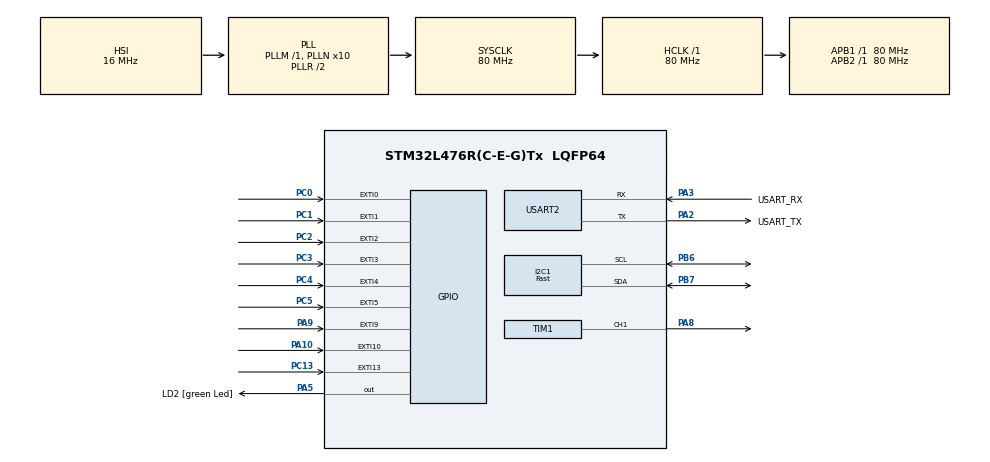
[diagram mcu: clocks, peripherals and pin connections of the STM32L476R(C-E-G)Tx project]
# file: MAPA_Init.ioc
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Dma.Request0=TIM1_CH1
Dma.TIM1_CH1.0.Direction=DMA_MEMORY_TO_PERIPH
Dma.TIM1_CH1.0.Instance=DMA1_Channel2
Dma.TIM1_CH1.0.MemDataAlignment=DMA_MDATAALIGN_HALFWORD
Dma.TIM1_CH1.0.MemInc=DMA_MINC_ENABLE
Dma.TIM1_CH1.0.Mode=DMA_NORMAL
Dma.TIM1_CH1.0.PeriphDataAlignment=DMA_PDATAALIGN_HALFWORD
Dma.TIM1_CH1.0.PeriphInc=DMA_PINC_DISABLE
Dma.TIM1_CH1.0.Priority=DMA_PRIORITY_VERY_HIGH
I2C1.I2C_Speed_Mode=I2C_Fast
I2C1.Timing=0x00702991
Mcu.Family=STM32L4
Mcu.Name=STM32L476R(C-E-G)Tx
Mcu.Package=LQFP64
NVIC.DMA1_Channel2_IRQn=true\:0\:0\:false\:false\:true\:false\:true\:true
NVIC.EXTI0_IRQn=true\:0\:0\:false\:false\:true\:true\:true\:true
NVIC.EXTI15_10_IRQn=true\:0\:0\:false\:false\:true\:true\:true\:true
NVIC.EXTI1_IRQn=true\:0\:0\:false\:false\:true\:true\:true\:true
NVIC.EXTI9_5_IRQn=true\:0\:0\:false\:false\:true\:true\:true\:true
NVIC.PriorityGroup=NVIC_PRIORITYGROUP_4
PA10.GPIO_ModeDefaultEXTI=GPIO_MODE_IT_FALLING
PA10.GPIO_PuPd=GPIO_PULLUP
PA10.Signal=GPXTI10
PA14\ (JTCK-SWCLK).GPIO_Label=TCK
PA14\ (JTCK-SWCLK).Signal=SYS_JTCK-SWCLK
PA2.GPIO_Label=USART_TX
PA2.GPIO_Mode=GPIO_MODE_AF_PP
PA2.GPIO_PuPd=GPIO_NOPULL
PA2.GPIO_Speed=GPIO_SPEED_FREQ_VERY_HIGH
PA2.Mode=Asynchronous
PA2.Signal=USART2_TX
PA3.GPIO_Label=USART_RX
PA3.GPIO_Mode=GPIO_MODE_AF_PP
PA3.GPIO_PuPd=GPIO_NOPULL
PA3.GPIO_Speed=GPIO_SPEED_FREQ_VERY_HIGH
PA3.Mode=Asynchronous
PA3.Signal=USART2_RX
PA5.GPIO_Label=LD2 [green Led]
PA5.GPIO_ModeDefaultOutputPP=GPIO_MODE_OUTPUT_PP
PA5.GPIO_PuPd=GPIO_PULLUP
PA5.GPIO_Speed=GPIO_SPEED_FREQ_LOW
PA5.Signal=GPIO_Output
PA8.Signal=S_TIM1_CH1
PA9.GPIO_ModeDefaultEXTI=GPIO_MODE_IT_FALLING
PA9.GPIO_PuPd=GPIO_PULLUP
PA9.Signal=GPXTI9
PB3\ (JTDO-TRACESWO).GPIO_Label=SWO
PB3\ (JTDO-TRACESWO).Signal=SYS_JTDO-SWO
PB6.GPIO_Pu=GPIO_PULLUP
PB6.Mode=I2C
PB6.Signal=I2C1_SCL
PB7.GPIO_Pu=GPIO_PULLUP
PB7.Mode=I2C
PB7.Signal=I2C1_SDA
PC0.GPIO_PuPd=GPIO_PULLUP
PC0.Signal=GPXTI0
PC1.GPIO_PuPd=GPIO_PULLUP
PC1.Signal=GPXTI1
PC13.GPIO_ModeDefaultEXTI=GPIO_MODE_IT_FALLING
PC13.GPIO_PuPd=GPIO_PULLUP
PC13.Signal=GPXTI13
PC2.GPIO_PuPd=GPIO_PULLUP
PC2.Signal=GPXTI2
PC3.GPIO_PuPd=GPIO_PULLUP
PC3.Signal=GPXTI3
PC4.GPIO_PuPd=GPIO_PULLUP
PC4.Signal=GPXTI4
PC5.GPIO_PuPd=GPIO_PULLUP
PC5.Signal=GPXTI5
PH0-OSC_IN\ (PH0).Signal=RCC_OSC_IN
PH1-OSC_OUT\ (PH1).Signal=RCC_OSC_OUT
ProjectManager.HeapSize=0x200
ProjectManager.StackSize=0x400
ProjectManager.TargetToolchain=STM32CubeIDE
RCC.ADCFreq_Value=64000000
RCC.AHBFreq_Value=80000000
RCC.APB1Freq_Value=80000000
RCC.APB1TimFreq_Value=80000000
RCC.APB2Freq_Value=80000000
RCC.APB2TimFreq_Value=80000000
RCC.CortexFreq_Value=80000000
RCC.HCLKFreq_Value=80000000
RCC.HSE_VALUE=8000000
RCC.HSI_VALUE=16000000
RCC.LSE_VALUE=32768
RCC.MSI_VALUE=4000000
RCC.PLLN=10
RCC.PLLSourceVirtual=RCC_PLLSOURCE_HSI
RCC.PREFETCH_ENABLE=1
RCC.SYSCLKFreq_VALUE=80000000
RCC.SYSCLKSource=RCC_SYSCLKSOURCE_PLLCLK
RCC.USBFreq_Value=64000000
RCC.VCOOutputFreq_Value=160000000
SH.S_TIM1_CH1.0=TIM1_CH1,PWM Generation1 CH1
TIM1.Channel-PWM\ Generation1\ CH1=TIM_CHANNEL_1
TIM1.Period=199
USART2.VirtualMode-Asynchronous=VM_ASYNC
VP_TIM1_VS_ClockSourceINT.Mode=Internal
board=NUCLEO-L476RG

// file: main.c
/* USER CODE BEGIN Header */
/**
  ******************************************************************************
  * @file           : main.c
  * @brief          : Main program body
  ******************************************************************************
  * @attention
  *
  * Copyright (c) 2024 STMicroelectronics.
  * All rights reserved.
  *
  * This software is licensed under terms that can be found in the LICENSE file
  * in the root directory of this software component.
  * If no LICENSE file comes with this software, it is provided AS-IS.
  *
  ******************************************************************************
  */
/* USER CODE END Header */
#include "main.h"

/* USER CODE BEGIN Includes */
#include "stm32l4xx_hal.h"
#include "brillez.h"
#include "ecran.h"
#include "string.h"
#include <stdio.h>
#include "midi_parser.h"
#include "init.h"
/* USER CODE END Includes */

I2C_HandleTypeDef hi2c1;

TIM_HandleTypeDef htim1;
DMA_HandleTypeDef hdma_tim1_ch1;

UART_HandleTypeDef huart2;

/* USER CODE BEGIN PV */
int __io_putchar(int ch) {
    HAL_UART_Transmit(&huart2, (uint8_t *)&ch, 1, HAL_MAX_DELAY);
    return ch;
}

/* USER CODE END PV */

void SystemClock_Config(void);
static void MX_GPIO_Init(void);
static void MX_DMA_Init(void);
static void MX_USART2_UART_Init(void);
static void MX_TIM1_Init(void);
static void MX_I2C1_Init(void);

int main(void)
{

  /* MCU Configuration--------------------------------------------------------*/

  /* Reset of all peripherals, Initializes the Flash interface and the Systick. */
  HAL_Init();

  /* Configure the system clock */
  SystemClock_Config();

  /* Initialize all configured peripherals */
  MX_GPIO_Init();
  MX_DMA_Init();
  MX_USART2_UART_Init();
  MX_TIM1_Init();
  MX_I2C1_Init();
  /* USER CODE BEGIN 2 */
  brillez_init();

  LCD_Init();
  LCD_Clear();

	LCD_SetRGB(40, 130, 255);  // Bleu

     // Boucle principale

  /* USER CODE END 2 */

  /* Infinite loop */
  /* USER CODE BEGIN WHILE */
	  assignement();
	  printf("fin assignement \r\n");

	  Navigation();

  while (1)
  {

/*			HAL_Delay(50);

	  		LCD_Clear();  // Efface l’écran avant d’écrire

	  		LCD_PrintFormatted("LED numero %lu", compteur);  // Affiche le compteur
	  		HAL_Delay(500);

	  		printf("Liste des sauvegardes : ");
	  		for (uint32_t i = 0; i < sauvegarde_index; i++) {
	  		  printf("%ld ", compteur_sauvegarde[i]);
	  		}
	  		printf("\r\n");

	  		light_up_led(compteur, 0xFF0000, 100);

	  		for (uint32_t i = 0; i < sauvegarde_index; i++) {
	  		  ws2812b_set_led_hex(&h_ws2812b,compteur_sauvegarde[i], 0x00FF00);
	  		}
*/

    /* USER CODE END WHILE */

  }
}

void SystemClock_Config(void)
{
  RCC_OscInitTypeDef RCC_OscInitStruct = {0};
  RCC_ClkInitTypeDef RCC_ClkInitStruct = {0};

  /** Configure the main internal regulator output voltage
  */
  if (HAL_PWREx_ControlVoltageScaling(PWR_REGULATOR_VOLTAGE_SCALE1) != HAL_OK)
  {
    Error_Handler();
  }

  /** Initializes the RCC Oscillators according to the specified parameters
  * in the RCC_OscInitTypeDef structure.
  */
  RCC_OscInitStruct.OscillatorType = RCC_OSCILLATORTYPE_HSI;
  RCC_OscInitStruct.HSIState = RCC_HSI_ON;
  RCC_OscInitStruct.HSICalibrationValue = RCC_HSICALIBRATION_DEFAULT;
  RCC_OscInitStruct.PLL.PLLState = RCC_PLL_ON;
  RCC_OscInitStruct.PLL.PLLSource = RCC_PLLSOURCE_HSI;
  RCC_OscInitStruct.PLL.PLLM = 1;
  RCC_OscInitStruct.PLL.PLLN = 10;
  RCC_OscInitStruct.PLL.PLLP = RCC_PLLP_DIV7;
  RCC_OscInitStruct.PLL.PLLQ = RCC_PLLQ_DIV2;
  RCC_OscInitStruct.PLL.PLLR = RCC_PLLR_DIV2;
  if (HAL_RCC_OscConfig(&RCC_OscInitStruct) != HAL_OK)
  {
    Error_Handler();
  }

  /** Initializes the CPU, AHB and APB buses clocks
  */
  RCC_ClkInitStruct.ClockType = RCC_CLOCKTYPE_HCLK|RCC_CLOCKTYPE_SYSCLK
                              |RCC_CLOCKTYPE_PCLK1|RCC_CLOCKTYPE_PCLK2;
  RCC_ClkInitStruct.SYSCLKSource = RCC_SYSCLKSOURCE_PLLCLK;
  RCC_ClkInitStruct.AHBCLKDivider = RCC_SYSCLK_DIV1;
  RCC_ClkInitStruct.APB1CLKDivider = RCC_HCLK_DIV1;
  RCC_ClkInitStruct.APB2CLKDivider = RCC_HCLK_DIV1;

  if (HAL_RCC_ClockConfig(&RCC_ClkInitStruct, FLASH_LATENCY_4) != HAL_OK)
  {
    Error_Handler();
  }
}

static void MX_I2C1_Init(void)
{

  hi2c1.Instance = I2C1;
  hi2c1.Init.Timing = 0x00702991;
  hi2c1.Init.OwnAddress1 = 0;
  hi2c1.Init.AddressingMode = I2C_ADDRESSINGMODE_7BIT;
  hi2c1.Init.DualAddressMode = I2C_DUALADDRESS_DISABLE;
  hi2c1.Init.OwnAddress2 = 0;
  hi2c1.Init.OwnAddress2Masks = I2C_OA2_NOMASK;
  hi2c1.Init.GeneralCallMode = I2C_GENERALCALL_DISABLE;
  hi2c1.Init.NoStretchMode = I2C_NOSTRETCH_DISABLE;
  if (HAL_I2C_Init(&hi2c1) != HAL_OK)
  {
    Error_Handler();
  }

  /** Configure Analogue filter
  */
  if (HAL_I2CEx_ConfigAnalogFilter(&hi2c1, I2C_ANALOGFILTER_ENABLE) != HAL_OK)
  {
    Error_Handler();
  }

  /** Configure Digital filter
  */
  if (HAL_I2CEx_ConfigDigitalFilter(&hi2c1, 0) != HAL_OK)
  {
    Error_Handler();
  }

}

static void MX_TIM1_Init(void)
{

  TIM_ClockConfigTypeDef sClockSourceConfig = {0};
  TIM_MasterConfigTypeDef sMasterConfig = {0};
  TIM_OC_InitTypeDef sConfigOC = {0};
  TIM_BreakDeadTimeConfigTypeDef sBreakDeadTimeConfig = {0};

  htim1.Instance = TIM1;
  htim1.Init.Prescaler = 0;
  htim1.Init.CounterMode = TIM_COUNTERMODE_UP;
  htim1.Init.Period = 199;
  htim1.Init.ClockDivision = TIM_CLOCKDIVISION_DIV1;
  htim1.Init.RepetitionCounter = 0;
  htim1.Init.AutoReloadPreload = TIM_AUTORELOAD_PRELOAD_DISABLE;
  if (HAL_TIM_Base_Init(&htim1) != HAL_OK)
  {
    Error_Handler();
  }
  sClockSourceConfig.ClockSource = TIM_CLOCKSOURCE_INTERNAL;
  if (HAL_TIM_ConfigClockSource(&htim1, &sClockSourceConfig) != HAL_OK)
  {
    Error_Handler();
  }
  if (HAL_TIM_PWM_Init(&htim1) != HAL_OK)
  {
    Error_Handler();
  }
  sMasterConfig.MasterOutputTrigger = TIM_TRGO_RESET;
  sMasterConfig.MasterOutputTrigger2 = TIM_TRGO2_RESET;
  sMasterConfig.MasterSlaveMode = TIM_MASTERSLAVEMODE_DISABLE;
  if (HAL_TIMEx_MasterConfigSynchronization(&htim1, &sMasterConfig) != HAL_OK)
  {
    Error_Handler();
  }
  sConfigOC.OCMode = TIM_OCMODE_PWM1;
  sConfigOC.Pulse = 0;
  sConfigOC.OCPolarity = TIM_OCPOLARITY_HIGH;
  sConfigOC.OCNPolarity = TIM_OCNPOLARITY_HIGH;
  sConfigOC.OCFastMode = TIM_OCFAST_DISABLE;
  sConfigOC.OCIdleState = TIM_OCIDLESTATE_RESET;
  sConfigOC.OCNIdleState = TIM_OCNIDLESTATE_RESET;
  if (HAL_TIM_PWM_ConfigChannel(&htim1, &sConfigOC, TIM_CHANNEL_1) != HAL_OK)
  {
    Error_Handler();
  }
  sBreakDeadTimeConfig.OffStateRunMode = TIM_OSSR_DISABLE;
  sBreakDeadTimeConfig.OffStateIDLEMode = TIM_OSSI_DISABLE;
  sBreakDeadTimeConfig.LockLevel = TIM_LOCKLEVEL_OFF;
  sBreakDeadTimeConfig.DeadTime = 0;
  sBreakDeadTimeConfig.BreakState = TIM_BREAK_DISABLE;
  sBreakDeadTimeConfig.BreakPolarity = TIM_BREAKPOLARITY_HIGH;
  sBreakDeadTimeConfig.BreakFilter = 0;
  sBreakDeadTimeConfig.Break2State = TIM_BREAK2_DISABLE;
  sBreakDeadTimeConfig.Break2Polarity = TIM_BREAK2POLARITY_HIGH;
  sBreakDeadTimeConfig.Break2Filter = 0;
  sBreakDeadTimeConfig.AutomaticOutput = TIM_AUTOMATICOUTPUT_DISABLE;
  if (HAL_TIMEx_ConfigBreakDeadTime(&htim1, &sBreakDeadTimeConfig) != HAL_OK)
  {
    Error_Handler();
  }
  HAL_TIM_MspPostInit(&htim1);

}

static void MX_USART2_UART_Init(void)
{

  huart2.Instance = USART2;
  huart2.Init.BaudRate = 115200;
  huart2.Init.WordLength = UART_WORDLENGTH_8B;
  huart2.Init.StopBits = UART_STOPBITS_1;
  huart2.Init.Parity = UART_PARITY_NONE;
  huart2.Init.Mode = UART_MODE_TX_RX;
  huart2.Init.HwFlowCtl = UART_HWCONTROL_NONE;
  huart2.Init.OverSampling = UART_OVERSAMPLING_16;
  huart2.Init.OneBitSampling = UART_ONE_BIT_SAMPLE_DISABLE;
  huart2.AdvancedInit.AdvFeatureInit = UART_ADVFEATURE_NO_INIT;
  if (HAL_UART_Init(&huart2) != HAL_OK)
  {
    Error_Handler();
  }

}

static void MX_DMA_Init(void)
{

  /* DMA controller clock enable */
  __HAL_RCC_DMA1_CLK_ENABLE();

  /* DMA interrupt init */
  /* DMA1_Channel2_IRQn interrupt configuration */
  HAL_NVIC_SetPriority(DMA1_Channel2_IRQn, 0, 0);
  HAL_NVIC_EnableIRQ(DMA1_Channel2_IRQn);

}

static void MX_GPIO_Init(void)
{
  GPIO_InitTypeDef GPIO_InitStruct = {0};

  /* GPIO Ports Clock Enable */
  __HAL_RCC_GPIOC_CLK_ENABLE();
  __HAL_RCC_GPIOH_CLK_ENABLE();
  __HAL_RCC_GPIOA_CLK_ENABLE();
  __HAL_RCC_GPIOB_CLK_ENABLE();

  /*Configure GPIO pin Output Level */
  HAL_GPIO_WritePin(LD2_GPIO_Port, LD2_Pin, GPIO_PIN_RESET);

  /*Configure GPIO pin : PC13 */
  GPIO_InitStruct.Pin = GPIO_PIN_13;
  GPIO_InitStruct.Mode = GPIO_MODE_IT_FALLING;
  GPIO_InitStruct.Pull = GPIO_PULLUP;
  HAL_GPIO_Init(GPIOC, &GPIO_InitStruct);

  /*Configure GPIO pins : PA0 PA1 PA9 PA10 */
  GPIO_InitStruct.Pin = GPIO_PIN_0|GPIO_PIN_1|GPIO_PIN_9|GPIO_PIN_10;
  GPIO_InitStruct.Mode = GPIO_MODE_IT_FALLING;
  GPIO_InitStruct.Pull = GPIO_PULLUP;
  HAL_GPIO_Init(GPIOA, &GPIO_InitStruct);

  /*Configure GPIO pin : LD2_Pin */
  GPIO_InitStruct.Pin = LD2_Pin;
  GPIO_InitStruct.Mode = GPIO_MODE_OUTPUT_PP;
  GPIO_InitStruct.Pull = GPIO_PULLUP;
  GPIO_InitStruct.Speed = GPIO_SPEED_FREQ_LOW;
  HAL_GPIO_Init(LD2_GPIO_Port, &GPIO_InitStruct);

  /* EXTI interrupt init*/
  HAL_NVIC_SetPriority(EXTI0_IRQn, 0, 0);
  HAL_NVIC_EnableIRQ(EXTI0_IRQn);

  HAL_NVIC_SetPriority(EXTI1_IRQn, 0, 0);
  HAL_NVIC_EnableIRQ(EXTI1_IRQn);

  HAL_NVIC_SetPriority(EXTI9_5_IRQn, 0, 0);
  HAL_NVIC_EnableIRQ(EXTI9_5_IRQn);

  HAL_NVIC_SetPriority(EXTI15_10_IRQn, 0, 0);
  HAL_NVIC_EnableIRQ(EXTI15_10_IRQn);

}

void Error_Handler(void)
{
  __disable_irq();
  while (1)
  {
  }
}
